VERSION 5.7 ;
  NOWIREEXTENSIONATPIN ON ;
  DIVIDERCHAR "/" ;
  BUSBITCHARS "[]" ;
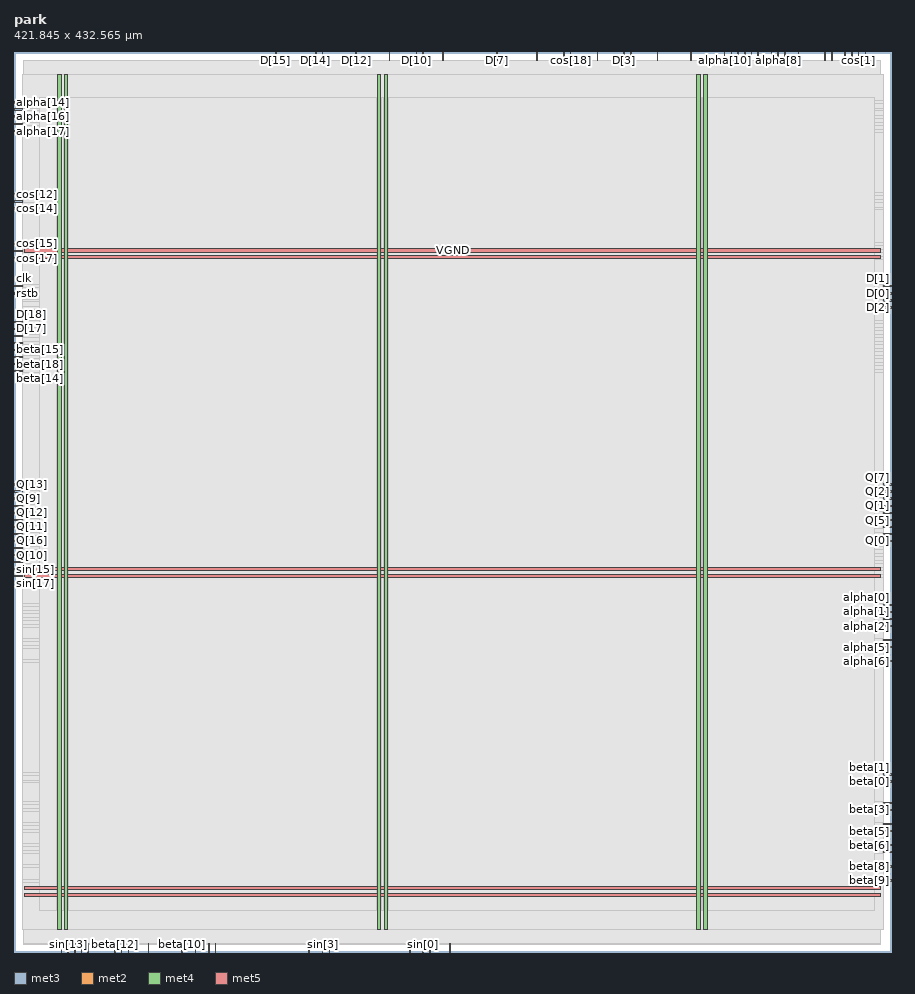
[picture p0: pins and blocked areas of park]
MACRO park
  CLASS BLOCK ;
  FOREIGN park ;
  ORIGIN 0.000 0.000 ;
  SIZE 421.845 BY 432.565 ;
  PIN D[0]
    DIRECTION OUTPUT ;
    USE SIGNAL ;
    ANTENNADIFFAREA 0.795200 ;
    PORT
      LAYER met3 ;
        RECT 417.845 316.240 421.845 316.840 ;
    END
  END D[0]
  PIN D[10]
    DIRECTION OUTPUT ;
    USE SIGNAL ;
    ANTENNADIFFAREA 0.795200 ;
    PORT
      LAYER met2 ;
        RECT 193.290 428.565 193.570 432.565 ;
    END
  END D[10]
  PIN D[11]
    DIRECTION OUTPUT ;
    USE SIGNAL ;
    ANTENNADIFFAREA 0.795200 ;
    PORT
      LAYER met2 ;
        RECT 180.410 428.565 180.690 432.565 ;
    END
  END D[11]
  PIN D[12]
    DIRECTION OUTPUT ;
    USE SIGNAL ;
    ANTENNADIFFAREA 0.795200 ;
    PORT
      LAYER met2 ;
        RECT 164.310 428.565 164.590 432.565 ;
    END
  END D[12]
  PIN D[13]
    DIRECTION OUTPUT ;
    USE SIGNAL ;
    ANTENNADIFFAREA 0.795200 ;
    PORT
      LAYER met2 ;
        RECT 148.210 428.565 148.490 432.565 ;
    END
  END D[13]
  PIN D[14]
    DIRECTION OUTPUT ;
    USE SIGNAL ;
    ANTENNADIFFAREA 0.795200 ;
    PORT
      LAYER met2 ;
        RECT 144.990 428.565 145.270 432.565 ;
    END
  END D[14]
  PIN D[15]
    DIRECTION OUTPUT ;
    USE SIGNAL ;
    ANTENNADIFFAREA 0.795200 ;
    PORT
      LAYER met2 ;
        RECT 125.670 428.565 125.950 432.565 ;
    END
  END D[15]
  PIN D[16]
    DIRECTION OUTPUT ;
    USE SIGNAL ;
    ANTENNADIFFAREA 0.795200 ;
    PORT
      LAYER met3 ;
        RECT 0.000 295.840 4.000 296.440 ;
    END
  END D[16]
  PIN D[17]
    DIRECTION OUTPUT ;
    USE SIGNAL ;
    ANTENNADIFFAREA 0.795200 ;
    PORT
      LAYER met3 ;
        RECT 0.000 299.240 4.000 299.840 ;
    END
  END D[17]
  PIN D[18]
    DIRECTION OUTPUT ;
    USE SIGNAL ;
    ANTENNADIFFAREA 0.795200 ;
    PORT
      LAYER met3 ;
        RECT 0.000 302.640 4.000 303.240 ;
    END
  END D[18]
  PIN D[1]
    DIRECTION OUTPUT ;
    USE SIGNAL ;
    ANTENNADIFFAREA 0.795200 ;
    PORT
      LAYER met3 ;
        RECT 417.845 319.640 421.845 320.240 ;
    END
  END D[1]
  PIN D[2]
    DIRECTION OUTPUT ;
    USE SIGNAL ;
    ANTENNADIFFAREA 0.795200 ;
    PORT
      LAYER met3 ;
        RECT 417.845 312.840 421.845 313.440 ;
    END
  END D[2]
  PIN D[3]
    DIRECTION OUTPUT ;
    USE SIGNAL ;
    ANTENNADIFFAREA 0.795200 ;
    PORT
      LAYER met2 ;
        RECT 293.110 428.565 293.390 432.565 ;
    END
  END D[3]
  PIN D[4]
    DIRECTION OUTPUT ;
    USE SIGNAL ;
    ANTENNADIFFAREA 0.795200 ;
    PORT
      LAYER met2 ;
        RECT 280.230 428.565 280.510 432.565 ;
    END
  END D[4]
  PIN D[5]
    DIRECTION OUTPUT ;
    USE SIGNAL ;
    ANTENNADIFFAREA 0.795200 ;
    PORT
      LAYER met2 ;
        RECT 264.130 428.565 264.410 432.565 ;
    END
  END D[5]
  PIN D[6]
    DIRECTION OUTPUT ;
    USE SIGNAL ;
    ANTENNADIFFAREA 0.795200 ;
    PORT
      LAYER met2 ;
        RECT 251.250 428.565 251.530 432.565 ;
    END
  END D[6]
  PIN D[7]
    DIRECTION OUTPUT ;
    USE SIGNAL ;
    ANTENNADIFFAREA 0.795200 ;
    PORT
      LAYER met2 ;
        RECT 231.930 428.565 232.210 432.565 ;
    END
  END D[7]
  PIN D[8]
    DIRECTION OUTPUT ;
    USE SIGNAL ;
    ANTENNADIFFAREA 0.795200 ;
    PORT
      LAYER met2 ;
        RECT 206.170 428.565 206.450 432.565 ;
    END
  END D[8]
  PIN D[9]
    DIRECTION OUTPUT ;
    USE SIGNAL ;
    ANTENNADIFFAREA 0.795200 ;
    PORT
      LAYER met2 ;
        RECT 196.510 428.565 196.790 432.565 ;
    END
  END D[9]
  PIN Q[0]
    DIRECTION OUTPUT ;
    USE SIGNAL ;
    ANTENNADIFFAREA 0.445500 ;
    PORT
      LAYER met3 ;
        RECT 417.845 197.240 421.845 197.840 ;
    END
  END Q[0]
  PIN Q[10]
    DIRECTION OUTPUT ;
    USE SIGNAL ;
    ANTENNADIFFAREA 0.795200 ;
    PORT
      LAYER met3 ;
        RECT 0.000 190.440 4.000 191.040 ;
    END
  END Q[10]
  PIN Q[11]
    DIRECTION OUTPUT ;
    USE SIGNAL ;
    ANTENNADIFFAREA 0.795200 ;
    PORT
      LAYER met3 ;
        RECT 0.000 204.040 4.000 204.640 ;
    END
  END Q[11]
  PIN Q[12]
    DIRECTION OUTPUT ;
    USE SIGNAL ;
    ANTENNADIFFAREA 0.795200 ;
    PORT
      LAYER met3 ;
        RECT 0.000 210.840 4.000 211.440 ;
    END
  END Q[12]
  PIN Q[13]
    DIRECTION OUTPUT ;
    USE SIGNAL ;
    ANTENNADIFFAREA 0.795200 ;
    PORT
      LAYER met3 ;
        RECT 0.000 224.440 4.000 225.040 ;
    END
  END Q[13]
  PIN Q[14]
    DIRECTION OUTPUT ;
    USE SIGNAL ;
    ANTENNADIFFAREA 0.795200 ;
    PORT
      LAYER met3 ;
        RECT 0.000 193.840 4.000 194.440 ;
    END
  END Q[14]
  PIN Q[15]
    DIRECTION OUTPUT ;
    USE SIGNAL ;
    ANTENNADIFFAREA 0.795200 ;
    PORT
      LAYER met3 ;
        RECT 0.000 207.440 4.000 208.040 ;
    END
  END Q[15]
  PIN Q[16]
    DIRECTION OUTPUT ;
    USE SIGNAL ;
    ANTENNADIFFAREA 0.795200 ;
    PORT
      LAYER met3 ;
        RECT 0.000 197.240 4.000 197.840 ;
    END
  END Q[16]
  PIN Q[17]
    DIRECTION OUTPUT ;
    USE SIGNAL ;
    ANTENNADIFFAREA 0.795200 ;
    PORT
      LAYER met3 ;
        RECT 0.000 200.640 4.000 201.240 ;
    END
  END Q[17]
  PIN Q[18]
    DIRECTION OUTPUT ;
    USE SIGNAL ;
    ANTENNADIFFAREA 0.795200 ;
    PORT
      LAYER met3 ;
        RECT 0.000 221.040 4.000 221.640 ;
    END
  END Q[18]
  PIN Q[1]
    DIRECTION OUTPUT ;
    USE SIGNAL ;
    ANTENNADIFFAREA 0.445500 ;
    PORT
      LAYER met3 ;
        RECT 417.845 214.240 421.845 214.840 ;
    END
  END Q[1]
  PIN Q[2]
    DIRECTION OUTPUT ;
    USE SIGNAL ;
    ANTENNADIFFAREA 0.445500 ;
    PORT
      LAYER met3 ;
        RECT 417.845 221.040 421.845 221.640 ;
    END
  END Q[2]
  PIN Q[3]
    DIRECTION OUTPUT ;
    USE SIGNAL ;
    ANTENNADIFFAREA 0.445500 ;
    PORT
      LAYER met3 ;
        RECT 417.845 217.640 421.845 218.240 ;
    END
  END Q[3]
  PIN Q[4]
    DIRECTION OUTPUT ;
    USE SIGNAL ;
    ANTENNADIFFAREA 0.445500 ;
    PORT
      LAYER met3 ;
        RECT 417.845 200.640 421.845 201.240 ;
    END
  END Q[4]
  PIN Q[5]
    DIRECTION OUTPUT ;
    USE SIGNAL ;
    ANTENNADIFFAREA 0.445500 ;
    PORT
      LAYER met3 ;
        RECT 417.845 210.840 421.845 211.440 ;
    END
  END Q[5]
  PIN Q[6]
    DIRECTION OUTPUT ;
    USE SIGNAL ;
    ANTENNADIFFAREA 0.445500 ;
    PORT
      LAYER met3 ;
        RECT 417.845 207.440 421.845 208.040 ;
    END
  END Q[6]
  PIN Q[7]
    DIRECTION OUTPUT ;
    USE SIGNAL ;
    ANTENNADIFFAREA 0.445500 ;
    PORT
      LAYER met3 ;
        RECT 417.845 224.440 421.845 225.040 ;
    END
  END Q[7]
  PIN Q[8]
    DIRECTION OUTPUT ;
    USE SIGNAL ;
    ANTENNADIFFAREA 0.795200 ;
    PORT
      LAYER met3 ;
        RECT 0.000 214.240 4.000 214.840 ;
    END
  END Q[8]
  PIN Q[9]
    DIRECTION OUTPUT ;
    USE SIGNAL ;
    ANTENNADIFFAREA 0.795200 ;
    PORT
      LAYER met3 ;
        RECT 0.000 217.640 4.000 218.240 ;
    END
  END Q[9]
  PIN VGND
    DIRECTION INOUT ;
    USE GROUND ;
    PORT
      LAYER met4 ;
        RECT 24.340 10.640 25.940 421.840 ;
    END
    PORT
      LAYER met4 ;
        RECT 177.940 10.640 179.540 421.840 ;
    END
    PORT
      LAYER met4 ;
        RECT 331.540 10.640 333.140 421.840 ;
    END
    PORT
      LAYER met5 ;
        RECT 5.280 30.030 416.540 31.630 ;
    END
    PORT
      LAYER met5 ;
        RECT 5.280 183.210 416.540 184.810 ;
    END
    PORT
      LAYER met5 ;
        RECT 5.280 336.390 416.540 337.990 ;
    END
  END VGND
  PIN VPWR
    DIRECTION INOUT ;
    USE POWER ;
    PORT
      LAYER met4 ;
        RECT 21.040 10.640 22.640 421.840 ;
    END
    PORT
      LAYER met4 ;
        RECT 174.640 10.640 176.240 421.840 ;
    END
    PORT
      LAYER met4 ;
        RECT 328.240 10.640 329.840 421.840 ;
    END
    PORT
      LAYER met5 ;
        RECT 5.280 26.730 416.540 28.330 ;
    END
    PORT
      LAYER met5 ;
        RECT 5.280 179.910 416.540 181.510 ;
    END
    PORT
      LAYER met5 ;
        RECT 5.280 333.090 416.540 334.690 ;
    END
  END VPWR
  PIN alpha[0]
    DIRECTION INPUT ;
    USE SIGNAL ;
    ANTENNAGATEAREA 0.196500 ;
    PORT
      LAYER met3 ;
        RECT 417.845 166.640 421.845 167.240 ;
    END
  END alpha[0]
  PIN alpha[10]
    DIRECTION INPUT ;
    USE SIGNAL ;
    ANTENNAGATEAREA 0.196500 ;
    PORT
      LAYER met2 ;
        RECT 341.410 428.565 341.690 432.565 ;
    END
  END alpha[10]
  PIN alpha[11]
    DIRECTION INPUT ;
    USE SIGNAL ;
    ANTENNAGATEAREA 0.196500 ;
    PORT
      LAYER met2 ;
        RECT 325.310 428.565 325.590 432.565 ;
    END
  END alpha[11]
  PIN alpha[12]
    DIRECTION INPUT ;
    USE SIGNAL ;
    ANTENNAGATEAREA 0.196500 ;
    PORT
      LAYER met2 ;
        RECT 309.210 428.565 309.490 432.565 ;
    END
  END alpha[12]
  PIN alpha[13]
    DIRECTION INPUT ;
    USE SIGNAL ;
    ANTENNAGATEAREA 0.196500 ;
    PORT
      LAYER met2 ;
        RECT 296.330 428.565 296.610 432.565 ;
    END
  END alpha[13]
  PIN alpha[14]
    DIRECTION INPUT ;
    USE SIGNAL ;
    ANTENNAGATEAREA 0.196500 ;
    PORT
      LAYER met3 ;
        RECT 0.000 408.040 4.000 408.640 ;
    END
  END alpha[14]
  PIN alpha[15]
    DIRECTION INPUT ;
    USE SIGNAL ;
    ANTENNAGATEAREA 0.196500 ;
    PORT
      LAYER met3 ;
        RECT 0.000 404.640 4.000 405.240 ;
    END
  END alpha[15]
  PIN alpha[16]
    DIRECTION INPUT ;
    USE SIGNAL ;
    ANTENNAGATEAREA 0.159000 ;
    PORT
      LAYER met3 ;
        RECT 0.000 401.240 4.000 401.840 ;
    END
  END alpha[16]
  PIN alpha[17]
    DIRECTION INPUT ;
    USE SIGNAL ;
    ANTENNAGATEAREA 0.196500 ;
    PORT
      LAYER met3 ;
        RECT 0.000 397.840 4.000 398.440 ;
    END
  END alpha[17]
  PIN alpha[18]
    DIRECTION INPUT ;
    USE SIGNAL ;
    ANTENNAGATEAREA 0.196500 ;
    PORT
      LAYER met3 ;
        RECT 0.000 394.440 4.000 395.040 ;
    END
  END alpha[18]
  PIN alpha[1]
    DIRECTION INPUT ;
    USE SIGNAL ;
    ANTENNAGATEAREA 0.196500 ;
    PORT
      LAYER met3 ;
        RECT 417.845 163.240 421.845 163.840 ;
    END
  END alpha[1]
  PIN alpha[2]
    DIRECTION INPUT ;
    USE SIGNAL ;
    ANTENNAGATEAREA 0.213000 ;
    PORT
      LAYER met3 ;
        RECT 417.845 159.840 421.845 160.440 ;
    END
  END alpha[2]
  PIN alpha[3]
    DIRECTION INPUT ;
    USE SIGNAL ;
    ANTENNAGATEAREA 0.213000 ;
    PORT
      LAYER met3 ;
        RECT 417.845 156.440 421.845 157.040 ;
    END
  END alpha[3]
  PIN alpha[4]
    DIRECTION INPUT ;
    USE SIGNAL ;
    ANTENNAGATEAREA 0.196500 ;
    PORT
      LAYER met3 ;
        RECT 417.845 149.640 421.845 150.240 ;
    END
  END alpha[4]
  PIN alpha[5]
    DIRECTION INPUT ;
    USE SIGNAL ;
    ANTENNAGATEAREA 0.196500 ;
    PORT
      LAYER met3 ;
        RECT 417.845 146.240 421.845 146.840 ;
    END
  END alpha[5]
  PIN alpha[6]
    DIRECTION INPUT ;
    USE SIGNAL ;
    ANTENNAGATEAREA 0.196500 ;
    PORT
      LAYER met3 ;
        RECT 417.845 139.440 421.845 140.040 ;
    END
  END alpha[6]
  PIN alpha[7]
    DIRECTION INPUT ;
    USE SIGNAL ;
    ANTENNAGATEAREA 0.196500 ;
    PORT
      LAYER met2 ;
        RECT 376.830 428.565 377.110 432.565 ;
    END
  END alpha[7]
  PIN alpha[8]
    DIRECTION INPUT ;
    USE SIGNAL ;
    ANTENNAGATEAREA 0.196500 ;
    PORT
      LAYER met2 ;
        RECT 367.170 428.565 367.450 432.565 ;
    END
  END alpha[8]
  PIN alpha[9]
    DIRECTION INPUT ;
    USE SIGNAL ;
    ANTENNAGATEAREA 0.196500 ;
    PORT
      LAYER met2 ;
        RECT 354.290 428.565 354.570 432.565 ;
    END
  END alpha[9]
  PIN beta[0]
    DIRECTION INPUT ;
    USE SIGNAL ;
    ANTENNAGATEAREA 0.159000 ;
    PORT
      LAYER met3 ;
        RECT 417.845 81.640 421.845 82.240 ;
    END
  END beta[0]
  PIN beta[10]
    DIRECTION INPUT ;
    USE SIGNAL ;
    ANTENNAGATEAREA 0.213000 ;
    PORT
      LAYER met2 ;
        RECT 80.590 0.000 80.870 4.000 ;
    END
  END beta[10]
  PIN beta[11]
    DIRECTION INPUT ;
    USE SIGNAL ;
    ANTENNAGATEAREA 0.213000 ;
    PORT
      LAYER met2 ;
        RECT 64.490 0.000 64.770 4.000 ;
    END
  END beta[11]
  PIN beta[12]
    DIRECTION INPUT ;
    USE SIGNAL ;
    ANTENNAGATEAREA 0.247500 ;
    PORT
      LAYER met2 ;
        RECT 48.390 0.000 48.670 4.000 ;
    END
  END beta[12]
  PIN beta[13]
    DIRECTION INPUT ;
    USE SIGNAL ;
    ANTENNAGATEAREA 0.213000 ;
    PORT
      LAYER met2 ;
        RECT 29.070 0.000 29.350 4.000 ;
    END
  END beta[13]
  PIN beta[14]
    DIRECTION INPUT ;
    USE SIGNAL ;
    ANTENNAGATEAREA 0.196500 ;
    PORT
      LAYER met3 ;
        RECT 0.000 278.840 4.000 279.440 ;
    END
  END beta[14]
  PIN beta[15]
    DIRECTION INPUT ;
    USE SIGNAL ;
    ANTENNAGATEAREA 0.196500 ;
    PORT
      LAYER met3 ;
        RECT 0.000 289.040 4.000 289.640 ;
    END
  END beta[15]
  PIN beta[16]
    DIRECTION INPUT ;
    USE SIGNAL ;
    ANTENNAGATEAREA 0.126000 ;
    PORT
      LAYER met3 ;
        RECT 0.000 285.640 4.000 286.240 ;
    END
  END beta[16]
  PIN beta[17]
    DIRECTION INPUT ;
    USE SIGNAL ;
    ANTENNAGATEAREA 0.196500 ;
    PORT
      LAYER met3 ;
        RECT 0.000 292.440 4.000 293.040 ;
    END
  END beta[17]
  PIN beta[18]
    DIRECTION INPUT ;
    USE SIGNAL ;
    ANTENNAGATEAREA 0.213000 ;
    PORT
      LAYER met3 ;
        RECT 0.000 282.240 4.000 282.840 ;
    END
  END beta[18]
  PIN beta[1]
    DIRECTION INPUT ;
    USE SIGNAL ;
    ANTENNAGATEAREA 0.196500 ;
    PORT
      LAYER met3 ;
        RECT 417.845 85.040 421.845 85.640 ;
    END
  END beta[1]
  PIN beta[2]
    DIRECTION INPUT ;
    USE SIGNAL ;
    ANTENNAGATEAREA 0.196500 ;
    PORT
      LAYER met3 ;
        RECT 417.845 71.440 421.845 72.040 ;
    END
  END beta[2]
  PIN beta[3]
    DIRECTION INPUT ;
    USE SIGNAL ;
    ANTENNAGATEAREA 0.196500 ;
    PORT
      LAYER met3 ;
        RECT 417.845 68.040 421.845 68.640 ;
    END
  END beta[3]
  PIN beta[4]
    DIRECTION INPUT ;
    USE SIGNAL ;
    ANTENNAGATEAREA 0.196500 ;
    PORT
      LAYER met3 ;
        RECT 417.845 61.240 421.845 61.840 ;
    END
  END beta[4]
  PIN beta[5]
    DIRECTION INPUT ;
    USE SIGNAL ;
    ANTENNAGATEAREA 0.213000 ;
    PORT
      LAYER met3 ;
        RECT 417.845 57.840 421.845 58.440 ;
    END
  END beta[5]
  PIN beta[6]
    DIRECTION INPUT ;
    USE SIGNAL ;
    ANTENNAGATEAREA 0.196500 ;
    PORT
      LAYER met3 ;
        RECT 417.845 51.040 421.845 51.640 ;
    END
  END beta[6]
  PIN beta[7]
    DIRECTION INPUT ;
    USE SIGNAL ;
    ANTENNAGATEAREA 0.196500 ;
    PORT
      LAYER met3 ;
        RECT 417.845 47.640 421.845 48.240 ;
    END
  END beta[7]
  PIN beta[8]
    DIRECTION INPUT ;
    USE SIGNAL ;
    ANTENNAGATEAREA 0.196500 ;
    PORT
      LAYER met3 ;
        RECT 417.845 40.840 421.845 41.440 ;
    END
  END beta[8]
  PIN beta[9]
    DIRECTION INPUT ;
    USE SIGNAL ;
    ANTENNAGATEAREA 0.196500 ;
    PORT
      LAYER met3 ;
        RECT 417.845 34.040 421.845 34.640 ;
    END
  END beta[9]
  PIN clk
    DIRECTION INPUT ;
    USE SIGNAL ;
    ANTENNAGATEAREA 0.852000 ;
    PORT
      LAYER met3 ;
        RECT 0.000 319.640 4.000 320.240 ;
    END
  END clk
  PIN cos[0]
    DIRECTION INPUT ;
    USE SIGNAL ;
    ANTENNAGATEAREA 0.159000 ;
    PORT
      LAYER met2 ;
        RECT 409.030 428.565 409.310 432.565 ;
    END
  END cos[0]
  PIN cos[10]
    DIRECTION INPUT ;
    USE SIGNAL ;
    ANTENNAGATEAREA 0.159000 ;
    PORT
      LAYER met2 ;
        RECT 347.850 428.565 348.130 432.565 ;
    END
  END cos[10]
  PIN cos[11]
    DIRECTION INPUT ;
    USE SIGNAL ;
    ANTENNAGATEAREA 0.196500 ;
    PORT
      LAYER met2 ;
        RECT 344.630 428.565 344.910 432.565 ;
    END
  END cos[11]
  PIN cos[12]
    DIRECTION INPUT ;
    USE SIGNAL ;
    ANTENNAGATEAREA 0.196500 ;
    PORT
      LAYER met3 ;
        RECT 0.000 363.840 4.000 364.440 ;
    END
  END cos[12]
  PIN cos[13]
    DIRECTION INPUT ;
    USE SIGNAL ;
    ANTENNAGATEAREA 0.196500 ;
    PORT
      LAYER met3 ;
        RECT 0.000 360.440 4.000 361.040 ;
    END
  END cos[13]
  PIN cos[14]
    DIRECTION INPUT ;
    USE SIGNAL ;
    ANTENNAGATEAREA 0.213000 ;
    PORT
      LAYER met3 ;
        RECT 0.000 357.040 4.000 357.640 ;
    END
  END cos[14]
  PIN cos[15]
    DIRECTION INPUT ;
    USE SIGNAL ;
    ANTENNAGATEAREA 0.213000 ;
    PORT
      LAYER met3 ;
        RECT 0.000 340.040 4.000 340.640 ;
    END
  END cos[15]
  PIN cos[16]
    DIRECTION INPUT ;
    USE SIGNAL ;
    ANTENNAGATEAREA 0.126000 ;
    PORT
      LAYER met3 ;
        RECT 0.000 336.640 4.000 337.240 ;
    END
  END cos[16]
  PIN cos[17]
    DIRECTION INPUT ;
    USE SIGNAL ;
    ANTENNAGATEAREA 0.196500 ;
    PORT
      LAYER met3 ;
        RECT 0.000 333.240 4.000 333.840 ;
    END
  END cos[17]
  PIN cos[18]
    DIRECTION INPUT ;
    USE SIGNAL ;
    ANTENNAGATEAREA 0.213000 ;
    PORT
      LAYER met2 ;
        RECT 267.350 428.565 267.630 432.565 ;
    END
  END cos[18]
  PIN cos[1]
    DIRECTION INPUT ;
    USE SIGNAL ;
    ANTENNAGATEAREA 0.159000 ;
    PORT
      LAYER met2 ;
        RECT 405.810 428.565 406.090 432.565 ;
    END
  END cos[1]
  PIN cos[2]
    DIRECTION INPUT ;
    USE SIGNAL ;
    ANTENNAGATEAREA 0.213000 ;
    PORT
      LAYER met2 ;
        RECT 402.590 428.565 402.870 432.565 ;
    END
  END cos[2]
  PIN cos[3]
    DIRECTION INPUT ;
    USE SIGNAL ;
    ANTENNAGATEAREA 0.196500 ;
    PORT
      LAYER met2 ;
        RECT 399.370 428.565 399.650 432.565 ;
    END
  END cos[3]
  PIN cos[4]
    DIRECTION INPUT ;
    USE SIGNAL ;
    ANTENNAGATEAREA 0.196500 ;
    PORT
      LAYER met2 ;
        RECT 392.930 428.565 393.210 432.565 ;
    END
  END cos[4]
  PIN cos[5]
    DIRECTION INPUT ;
    USE SIGNAL ;
    ANTENNAGATEAREA 0.159000 ;
    PORT
      LAYER met2 ;
        RECT 389.710 428.565 389.990 432.565 ;
    END
  END cos[5]
  PIN cos[6]
    DIRECTION INPUT ;
    USE SIGNAL ;
    ANTENNAGATEAREA 0.196500 ;
    PORT
      LAYER met2 ;
        RECT 370.390 428.565 370.670 432.565 ;
    END
  END cos[6]
  PIN cos[7]
    DIRECTION INPUT ;
    USE SIGNAL ;
    ANTENNAGATEAREA 0.196500 ;
    PORT
      LAYER met2 ;
        RECT 363.950 428.565 364.230 432.565 ;
    END
  END cos[7]
  PIN cos[8]
    DIRECTION INPUT ;
    USE SIGNAL ;
    ANTENNAGATEAREA 0.196500 ;
    PORT
      LAYER met2 ;
        RECT 357.510 428.565 357.790 432.565 ;
    END
  END cos[8]
  PIN cos[9]
    DIRECTION INPUT ;
    USE SIGNAL ;
    ANTENNAGATEAREA 0.196500 ;
    PORT
      LAYER met2 ;
        RECT 351.070 428.565 351.350 432.565 ;
    END
  END cos[9]
  PIN done
    DIRECTION OUTPUT ;
    USE SIGNAL ;
    ANTENNADIFFAREA 0.445500 ;
    PORT
      LAYER met3 ;
        RECT 417.845 309.440 421.845 310.040 ;
    END
  END done
  PIN rstb
    DIRECTION INPUT ;
    USE SIGNAL ;
    ANTENNAGATEAREA 0.213000 ;
    PORT
      LAYER met3 ;
        RECT 0.000 316.240 4.000 316.840 ;
    END
  END rstb
  PIN sin[0]
    DIRECTION INPUT ;
    USE SIGNAL ;
    ANTENNAGATEAREA 0.495000 ;
    PORT
      LAYER met2 ;
        RECT 196.510 0.000 196.790 4.000 ;
    END
  END sin[0]
  PIN sin[10]
    DIRECTION INPUT ;
    USE SIGNAL ;
    ANTENNAGATEAREA 0.196500 ;
    PORT
      LAYER met2 ;
        RECT 51.610 0.000 51.890 4.000 ;
    END
  END sin[10]
  PIN sin[11]
    DIRECTION INPUT ;
    USE SIGNAL ;
    ANTENNAGATEAREA 0.196500 ;
    PORT
      LAYER met2 ;
        RECT 35.510 0.000 35.790 4.000 ;
    END
  END sin[11]
  PIN sin[12]
    DIRECTION INPUT ;
    USE SIGNAL ;
    ANTENNAGATEAREA 0.213000 ;
    PORT
      LAYER met2 ;
        RECT 22.630 0.000 22.910 4.000 ;
    END
  END sin[12]
  PIN sin[13]
    DIRECTION INPUT ;
    USE SIGNAL ;
    ANTENNAGATEAREA 0.213000 ;
    PORT
      LAYER met2 ;
        RECT 25.850 0.000 26.130 4.000 ;
    END
  END sin[13]
  PIN sin[14]
    DIRECTION INPUT ;
    USE SIGNAL ;
    ANTENNAGATEAREA 0.213000 ;
    PORT
      LAYER met2 ;
        RECT 32.290 0.000 32.570 4.000 ;
    END
  END sin[14]
  PIN sin[15]
    DIRECTION INPUT ;
    USE SIGNAL ;
    ANTENNAGATEAREA 0.126000 ;
    PORT
      LAYER met3 ;
        RECT 0.000 187.040 4.000 187.640 ;
    END
  END sin[15]
  PIN sin[16]
    DIRECTION INPUT ;
    USE SIGNAL ;
    ANTENNAGATEAREA 0.126000 ;
    PORT
      LAYER met3 ;
        RECT 0.000 183.640 4.000 184.240 ;
    END
  END sin[16]
  PIN sin[17]
    DIRECTION INPUT ;
    USE SIGNAL ;
    ANTENNAGATEAREA 0.196500 ;
    PORT
      LAYER met3 ;
        RECT 0.000 180.240 4.000 180.840 ;
    END
  END sin[17]
  PIN sin[18]
    DIRECTION INPUT ;
    USE SIGNAL ;
    ANTENNAGATEAREA 0.213000 ;
    PORT
      LAYER met2 ;
        RECT 209.390 0.000 209.670 4.000 ;
    END
  END sin[18]
  PIN sin[1]
    DIRECTION INPUT ;
    USE SIGNAL ;
    ANTENNAGATEAREA 0.495000 ;
    PORT
      LAYER met2 ;
        RECT 199.730 0.000 200.010 4.000 ;
    END
  END sin[1]
  PIN sin[2]
    DIRECTION INPUT ;
    USE SIGNAL ;
    ANTENNAGATEAREA 0.196500 ;
    PORT
      LAYER met2 ;
        RECT 190.070 0.000 190.350 4.000 ;
    END
  END sin[2]
  PIN sin[3]
    DIRECTION INPUT ;
    USE SIGNAL ;
    ANTENNAGATEAREA 0.196500 ;
    PORT
      LAYER met2 ;
        RECT 148.210 0.000 148.490 4.000 ;
    END
  END sin[3]
  PIN sin[4]
    DIRECTION INPUT ;
    USE SIGNAL ;
    ANTENNAGATEAREA 0.213000 ;
    PORT
      LAYER met2 ;
        RECT 151.430 0.000 151.710 4.000 ;
    END
  END sin[4]
  PIN sin[5]
    DIRECTION INPUT ;
    USE SIGNAL ;
    ANTENNAGATEAREA 0.213000 ;
    PORT
      LAYER met2 ;
        RECT 141.770 0.000 142.050 4.000 ;
    END
  END sin[5]
  PIN sin[6]
    DIRECTION INPUT ;
    USE SIGNAL ;
    ANTENNAGATEAREA 0.196500 ;
    PORT
      LAYER met2 ;
        RECT 93.470 0.000 93.750 4.000 ;
    END
  END sin[6]
  PIN sin[7]
    DIRECTION INPUT ;
    USE SIGNAL ;
    ANTENNAGATEAREA 0.196500 ;
    PORT
      LAYER met2 ;
        RECT 96.690 0.000 96.970 4.000 ;
    END
  END sin[7]
  PIN sin[8]
    DIRECTION INPUT ;
    USE SIGNAL ;
    ANTENNAGATEAREA 0.213000 ;
    PORT
      LAYER met2 ;
        RECT 87.030 0.000 87.310 4.000 ;
    END
  END sin[8]
  PIN sin[9]
    DIRECTION INPUT ;
    USE SIGNAL ;
    ANTENNAGATEAREA 0.196500 ;
    PORT
      LAYER met2 ;
        RECT 54.830 0.000 55.110 4.000 ;
    END
  END sin[9]
  PIN start
    DIRECTION INPUT ;
    USE SIGNAL ;
    ANTENNAGATEAREA 0.196500 ;
    PORT
      LAYER met3 ;
        RECT 417.845 204.040 421.845 204.640 ;
    END
  END start
  OBS
      LAYER li1 ;
        RECT 5.520 10.795 416.300 421.685 ;
      LAYER met1 ;
        RECT 4.670 10.640 416.690 422.580 ;
      LAYER met2 ;
        RECT 4.690 428.285 125.390 428.565 ;
        RECT 126.230 428.285 144.710 428.565 ;
        RECT 145.550 428.285 147.930 428.565 ;
        RECT 148.770 428.285 164.030 428.565 ;
        RECT 164.870 428.285 180.130 428.565 ;
        RECT 180.970 428.285 193.010 428.565 ;
        RECT 193.850 428.285 196.230 428.565 ;
        RECT 197.070 428.285 205.890 428.565 ;
        RECT 206.730 428.285 231.650 428.565 ;
        RECT 232.490 428.285 250.970 428.565 ;
        RECT 251.810 428.285 263.850 428.565 ;
        RECT 264.690 428.285 267.070 428.565 ;
        RECT 267.910 428.285 279.950 428.565 ;
        RECT 280.790 428.285 292.830 428.565 ;
        RECT 293.670 428.285 296.050 428.565 ;
        RECT 296.890 428.285 308.930 428.565 ;
        RECT 309.770 428.285 325.030 428.565 ;
        RECT 325.870 428.285 341.130 428.565 ;
        RECT 341.970 428.285 344.350 428.565 ;
        RECT 345.190 428.285 347.570 428.565 ;
        RECT 348.410 428.285 350.790 428.565 ;
        RECT 351.630 428.285 354.010 428.565 ;
        RECT 354.850 428.285 357.230 428.565 ;
        RECT 358.070 428.285 363.670 428.565 ;
        RECT 364.510 428.285 366.890 428.565 ;
        RECT 367.730 428.285 370.110 428.565 ;
        RECT 370.950 428.285 376.550 428.565 ;
        RECT 377.390 428.285 389.430 428.565 ;
        RECT 390.270 428.285 392.650 428.565 ;
        RECT 393.490 428.285 399.090 428.565 ;
        RECT 399.930 428.285 402.310 428.565 ;
        RECT 403.150 428.285 405.530 428.565 ;
        RECT 406.370 428.285 408.750 428.565 ;
        RECT 409.590 428.285 416.670 428.565 ;
        RECT 4.690 4.280 416.670 428.285 ;
        RECT 4.690 3.670 22.350 4.280 ;
        RECT 23.190 3.670 25.570 4.280 ;
        RECT 26.410 3.670 28.790 4.280 ;
        RECT 29.630 3.670 32.010 4.280 ;
        RECT 32.850 3.670 35.230 4.280 ;
        RECT 36.070 3.670 48.110 4.280 ;
        RECT 48.950 3.670 51.330 4.280 ;
        RECT 52.170 3.670 54.550 4.280 ;
        RECT 55.390 3.670 64.210 4.280 ;
        RECT 65.050 3.670 80.310 4.280 ;
        RECT 81.150 3.670 86.750 4.280 ;
        RECT 87.590 3.670 93.190 4.280 ;
        RECT 94.030 3.670 96.410 4.280 ;
        RECT 97.250 3.670 141.490 4.280 ;
        RECT 142.330 3.670 147.930 4.280 ;
        RECT 148.770 3.670 151.150 4.280 ;
        RECT 151.990 3.670 189.790 4.280 ;
        RECT 190.630 3.670 196.230 4.280 ;
        RECT 197.070 3.670 199.450 4.280 ;
        RECT 200.290 3.670 209.110 4.280 ;
        RECT 209.950 3.670 416.670 4.280 ;
      LAYER met3 ;
        RECT 3.990 409.040 417.845 421.765 ;
        RECT 4.400 407.640 417.845 409.040 ;
        RECT 3.990 405.640 417.845 407.640 ;
        RECT 4.400 404.240 417.845 405.640 ;
        RECT 3.990 402.240 417.845 404.240 ;
        RECT 4.400 400.840 417.845 402.240 ;
        RECT 3.990 398.840 417.845 400.840 ;
        RECT 4.400 397.440 417.845 398.840 ;
        RECT 3.990 395.440 417.845 397.440 ;
        RECT 4.400 394.040 417.845 395.440 ;
        RECT 3.990 364.840 417.845 394.040 ;
        RECT 4.400 363.440 417.845 364.840 ;
        RECT 3.990 361.440 417.845 363.440 ;
        RECT 4.400 360.040 417.845 361.440 ;
        RECT 3.990 358.040 417.845 360.040 ;
        RECT 4.400 356.640 417.845 358.040 ;
        RECT 3.990 341.040 417.845 356.640 ;
        RECT 4.400 339.640 417.845 341.040 ;
        RECT 3.990 337.640 417.845 339.640 ;
        RECT 4.400 336.240 417.845 337.640 ;
        RECT 3.990 334.240 417.845 336.240 ;
        RECT 4.400 332.840 417.845 334.240 ;
        RECT 3.990 320.640 417.845 332.840 ;
        RECT 4.400 319.240 417.445 320.640 ;
        RECT 3.990 317.240 417.845 319.240 ;
        RECT 4.400 315.840 417.445 317.240 ;
        RECT 3.990 313.840 417.845 315.840 ;
        RECT 3.990 312.440 417.445 313.840 ;
        RECT 3.990 310.440 417.845 312.440 ;
        RECT 3.990 309.040 417.445 310.440 ;
        RECT 3.990 303.640 417.845 309.040 ;
        RECT 4.400 302.240 417.845 303.640 ;
        RECT 3.990 300.240 417.845 302.240 ;
        RECT 4.400 298.840 417.845 300.240 ;
        RECT 3.990 296.840 417.845 298.840 ;
        RECT 4.400 295.440 417.845 296.840 ;
        RECT 3.990 293.440 417.845 295.440 ;
        RECT 4.400 292.040 417.845 293.440 ;
        RECT 3.990 290.040 417.845 292.040 ;
        RECT 4.400 288.640 417.845 290.040 ;
        RECT 3.990 286.640 417.845 288.640 ;
        RECT 4.400 285.240 417.845 286.640 ;
        RECT 3.990 283.240 417.845 285.240 ;
        RECT 4.400 281.840 417.845 283.240 ;
        RECT 3.990 279.840 417.845 281.840 ;
        RECT 4.400 278.440 417.845 279.840 ;
        RECT 3.990 225.440 417.845 278.440 ;
        RECT 4.400 224.040 417.445 225.440 ;
        RECT 3.990 222.040 417.845 224.040 ;
        RECT 4.400 220.640 417.445 222.040 ;
        RECT 3.990 218.640 417.845 220.640 ;
        RECT 4.400 217.240 417.445 218.640 ;
        RECT 3.990 215.240 417.845 217.240 ;
        RECT 4.400 213.840 417.445 215.240 ;
        RECT 3.990 211.840 417.845 213.840 ;
        RECT 4.400 210.440 417.445 211.840 ;
        RECT 3.990 208.440 417.845 210.440 ;
        RECT 4.400 207.040 417.445 208.440 ;
        RECT 3.990 205.040 417.845 207.040 ;
        RECT 4.400 203.640 417.445 205.040 ;
        RECT 3.990 201.640 417.845 203.640 ;
        RECT 4.400 200.240 417.445 201.640 ;
        RECT 3.990 198.240 417.845 200.240 ;
        RECT 4.400 196.840 417.445 198.240 ;
        RECT 3.990 194.840 417.845 196.840 ;
        RECT 4.400 193.440 417.845 194.840 ;
        RECT 3.990 191.440 417.845 193.440 ;
        RECT 4.400 190.040 417.845 191.440 ;
        RECT 3.990 188.040 417.845 190.040 ;
        RECT 4.400 186.640 417.845 188.040 ;
        RECT 3.990 184.640 417.845 186.640 ;
        RECT 4.400 183.240 417.845 184.640 ;
        RECT 3.990 181.240 417.845 183.240 ;
        RECT 4.400 179.840 417.845 181.240 ;
        RECT 3.990 167.640 417.845 179.840 ;
        RECT 3.990 166.240 417.445 167.640 ;
        RECT 3.990 164.240 417.845 166.240 ;
        RECT 3.990 162.840 417.445 164.240 ;
        RECT 3.990 160.840 417.845 162.840 ;
        RECT 3.990 159.440 417.445 160.840 ;
        RECT 3.990 157.440 417.845 159.440 ;
        RECT 3.990 156.040 417.445 157.440 ;
        RECT 3.990 150.640 417.845 156.040 ;
        RECT 3.990 149.240 417.445 150.640 ;
        RECT 3.990 147.240 417.845 149.240 ;
        RECT 3.990 145.840 417.445 147.240 ;
        RECT 3.990 140.440 417.845 145.840 ;
        RECT 3.990 139.040 417.445 140.440 ;
        RECT 3.990 86.040 417.845 139.040 ;
        RECT 3.990 84.640 417.445 86.040 ;
        RECT 3.990 82.640 417.845 84.640 ;
        RECT 3.990 81.240 417.445 82.640 ;
        RECT 3.990 72.440 417.845 81.240 ;
        RECT 3.990 71.040 417.445 72.440 ;
        RECT 3.990 69.040 417.845 71.040 ;
        RECT 3.990 67.640 417.445 69.040 ;
        RECT 3.990 62.240 417.845 67.640 ;
        RECT 3.990 60.840 417.445 62.240 ;
        RECT 3.990 58.840 417.845 60.840 ;
        RECT 3.990 57.440 417.445 58.840 ;
        RECT 3.990 52.040 417.845 57.440 ;
        RECT 3.990 50.640 417.445 52.040 ;
        RECT 3.990 48.640 417.845 50.640 ;
        RECT 3.990 47.240 417.445 48.640 ;
        RECT 3.990 41.840 417.845 47.240 ;
        RECT 3.990 40.440 417.445 41.840 ;
        RECT 3.990 35.040 417.845 40.440 ;
        RECT 3.990 33.640 417.445 35.040 ;
        RECT 3.990 10.715 417.845 33.640 ;
      LAYER met4 ;
        RECT 12.255 19.895 20.640 410.545 ;
        RECT 23.040 19.895 23.940 410.545 ;
        RECT 26.340 19.895 174.240 410.545 ;
        RECT 176.640 19.895 177.540 410.545 ;
        RECT 179.940 19.895 327.840 410.545 ;
        RECT 330.240 19.895 331.140 410.545 ;
        RECT 333.540 19.895 413.705 410.545 ;
  END
END park
END LIBRARY

